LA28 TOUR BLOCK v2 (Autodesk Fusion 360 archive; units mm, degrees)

design "LA28 TOUR BLOCK" references "LA28 TOUR BLOCK.sldprt"
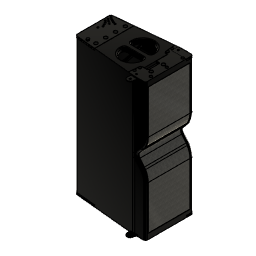
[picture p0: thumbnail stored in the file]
step "WorkingModel"
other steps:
derived_base_feature "Derived Base Feature" bodies "Fillet3"
named bodies: "Fillet3"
